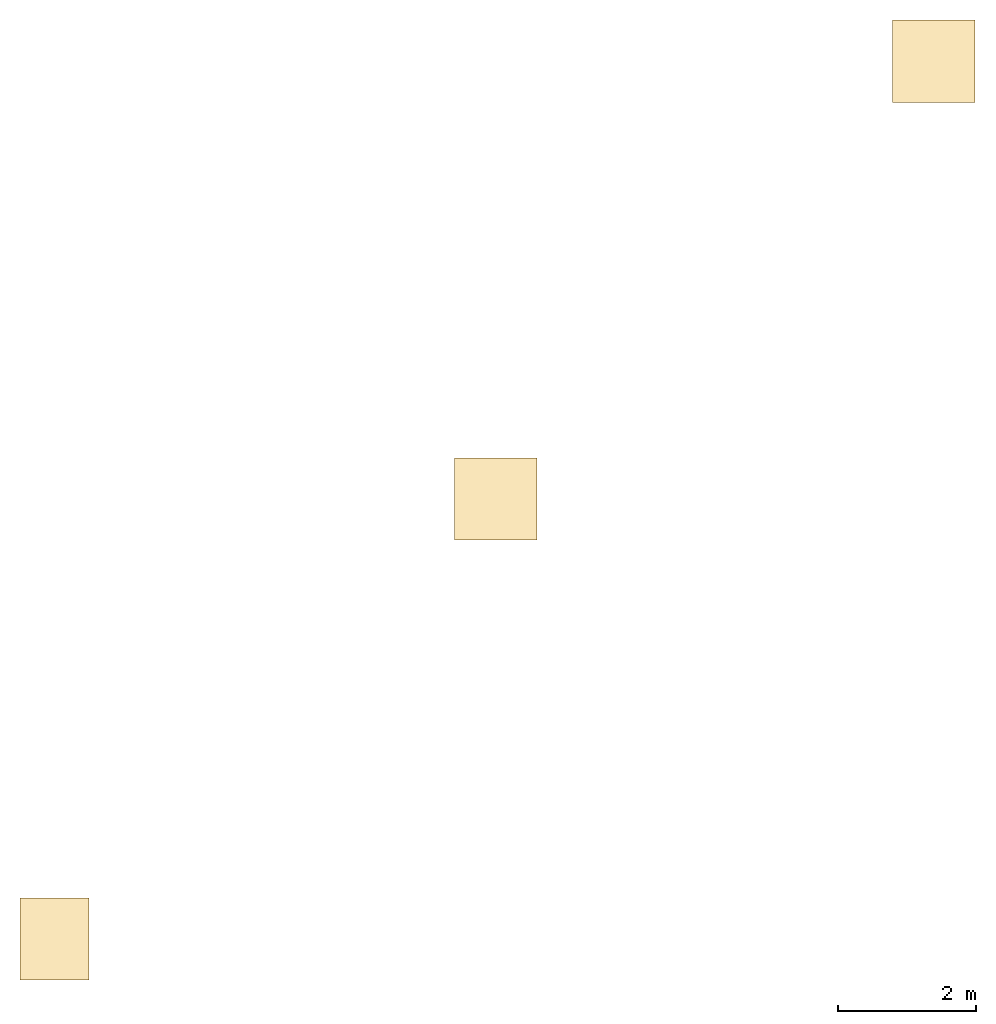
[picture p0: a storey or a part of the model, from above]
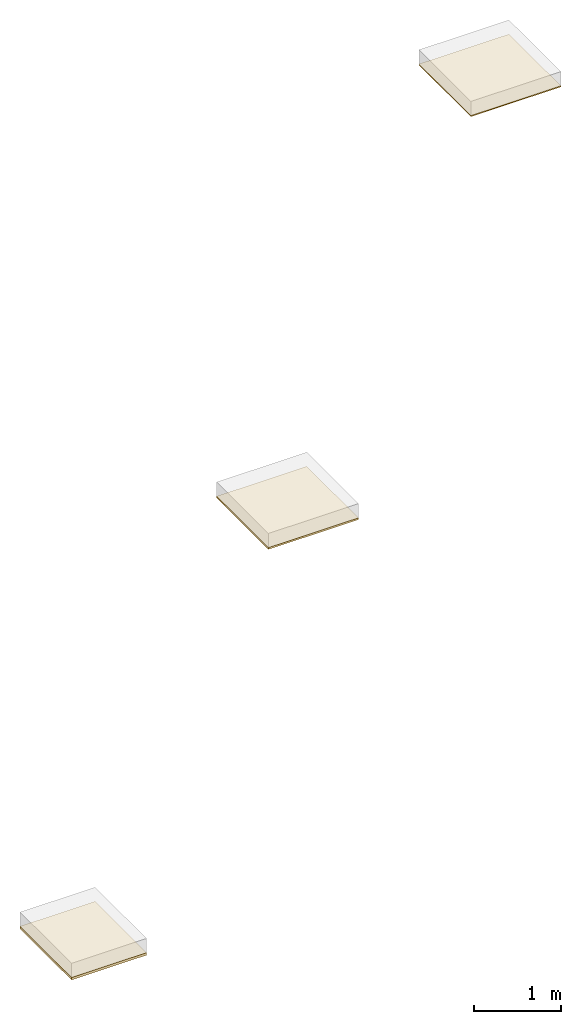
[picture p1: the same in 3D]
Properties of the parts of a building model (IFC2X3)

# File
Description: ViewDefinition [CoordinationView]
File name: 012345
Time: 2023-01-18T09:42:17
Written by: The EXPRESS Data Manager Version 5.02.0100.07 : 28 Aug 2013
Made in: 21.1.70.21 - Exporter 21.1.70.21 - Alternate UI 21.1.70.21
Comment: STEP Physical File produced by: The EXPRESS Data Manager Version 5.02.0100.07 : 28 Aug 2013 * Module: EDMstepFileFactory/EDMstandAlone * Creation date: Wed Jan 18 09:42:17 2023 * Host: BIM-LT03 * Database: C:\Users\DONNEE~1\AppData\Local\Temp\6dfd9f73-01cb-4fe2-bb7c-203e315a706e\6f2f6949-de90-4345-abf6-b3687df37d3c\ifc * Database version: 5507 * Database creation date: Wed Jan 18 09:42:17 2023 * Schema: IFC2X3 * Model: DataRepository.ifc * Model creation date: Wed Jan 18 09:42:17 2023 * Header model: DataRepository.ifc_HeaderModel * Header model creation date: Wed Jan 18 09:42:17 2023 * EDMuser: sdai-user * EDMgroup: sdai-group * License ID and type: 5605 : Permanent license. Expiry date: * EDMstepFileFactory options: 020000

# IfcProject, 012345
LongName: Cadix Project Naam; Phase: Cadix leeg V2.0

# IfcSite, Default
RefLatitude: 52, 3, 20, 225830; RefLongitude: 5, 6, 28, 692855; RefElevation: 0 mm
Pset_ProductRequirements - Category: Project Information

# IfcBuilding
Pset_BuildingCommon - NumberOfStoreys: 2
Pset_ProductRequirements - Category: Project Information

# IfcBuildingStorey: Level:niveau (2)
Pset_ProductRequirements - Category: Levels
Name | LongName = Pset_AirSideSystemInformation, Name = Pset_ProductRequirements, Name | Elevation (mm)
00 begane grond | 00 begane grond | -2.7707e-11
01 eerste verdieping | 01 eerste verdieping | 1200

# IfcCovering: Compound Ceiling:NLRS_45_CEI_Heraklith A2 afbouwpaneel 15x1200x600mm, Compound Ceiling:NLRS_45_CEI_Heraklith A2 afbouwpaneel 15x1200x600mm:888459
In: 01 eerste verdieping
Type - PredefinedType: CEILING
Type - Pset_CoveringCommon - Reference: Compound Ceiling:NLRS_45_CEI_Heraklith A2 afbouwpaneel 15x1200x600mm; TotalThickness: 15 mm
Type - Pset_ElementShading - Roughness: 304.8 mm
Type - Pset_ManufacturerTypeInformation - Manufacturer: Knauf Insulation B.V.
Type - Pset_ProductRequirements - Category: Ceilings
Type - Pset_QuantityTakeOff - Reference: Compound Ceiling:NLRS_45_CEI_Heraklith A2 afbouwpaneel 15x1200x600mm
Type - Ceiling Schedule LOD200 - Assembly Code: 45.0; Type Image: Raster image: Heraklith A2 Afbouwpaneel.jpg; Model: Heraklith® | A2 afbouwpaneel is een A2 houtwolcementpaneel; Manufacturer: Knauf Insulation B.V.; URL: www.heraklith.nl; Description: A2 afbouwpaneel - 15mm; phone: +31(0)162-421245; email: customerservice.nl@knaufinsulation.com; product URL: https://heraklith.nl/houtwol-producten/a2-afbouwpaneel; warmteweerstand: 0,15 (m2.K/W); NLRS_C_Code_Brandklasse: A2-s1,d0; brandweerstand: REI 60 mits verwerkt tegen massief beton conform classificatierapport nr 16210B / 16211B; geluidsabsorbtie: niet getest; DoP: W4302APCPR; NLRS_C_content_creator: Knauf Insulation; NLRS_C_content_versie: V1.0
Type - Pset_Ceiling Schedule LOD400 - gewicht KG/M2: 8.5; Assembly Code: 45.0; Type Image: Raster image: Heraklith A2 Afbouwpaneel.jpg; Model: Heraklith® | A2 afbouwpaneel is een A2 houtwolcementpaneel; Manufacturer: Knauf Insulation B.V.; URL: www.heraklith.nl; Description: A2 afbouwpaneel - 15mm; phone: +31(0)162-421245; email: customerservice.nl@knaufinsulation.com; product URL: https://heraklith.nl/houtwol-producten/a2-afbouwpaneel; warmteweerstand: 0,15 (m2.K/W); NLRS_C_Code_Brandklasse: A2-s1,d0; brandweerstand: REI 60 mits verwerkt tegen massief beton conform classificatierapport nr 16210B / 16211B; geluidsabsorbtie: niet getest; DoP: W4302APCPR; NLRS_C_content_creator: Knauf Insulation; NLRS_C_content_versie: V1.0; panelen per pallet: 70; pallet m2: 50.4 m2; vezelbreedte: standaard 2mm optie: 1mm; kleur: standaard natuurtint optie: Wit (RAL9003) / RAL; Druksterkte kPa: 200; Chloride gehalte: Cl3; Tolerantie: Dikte (T): (T1) +3/-2; Tolerantie: Lengte (L): (L2) +3/-5; Tolerantie: Breedte (W): (W1) +3/-3; Tolerantie: Haaksheid (S): (S2) ≤2; Tolerantie: Vlakheid (P): (P1) ≤6; Randafwerking: Isolatie: n.v.t.; Randafwerking: Houtwol: Facet: 5mm; CE-codering: WW-EN 13168-L2-W1-T1-S2-P2-CS(10/Y)200-Cl3
Classification: 45.0 (Uniformat); Material: Heraklith A2 afbouwpaneel - Houtwollaag - 1200x600mm 15 mm
Pset_CoveringCommon - Finish: Heraklith A2 afbouwpaneel - Houtwollaag - 1200x600mm;
Ceiling Schedule LOD200 - Type: Compound Ceiling: NLRS_45_CEI_Heraklith A2 afbouwpaneel 15x1200x600mm
Pset_Ceiling Schedule LOD400 - Type: Compound Ceiling: NLRS_45_CEI_Heraklith A2 afbouwpaneel 15x1200x600mm

# IfcCovering: Compound Ceiling:NLRS_45_CEI_Heraklith A2 afbouwpaneel 25x1200x600mm, Compound Ceiling:NLRS_45_CEI_Heraklith A2 afbouwpaneel 25x1200x600mm:912503
In: 01 eerste verdieping
Type - PredefinedType: CEILING
Type - Pset_CoveringCommon - Reference: Compound Ceiling:NLRS_45_CEI_Heraklith A2 afbouwpaneel 25x1200x600mm; TotalThickness: 25 mm
Type - Pset_ElementShading - Roughness: 304.8 mm
Type - Pset_ManufacturerTypeInformation - Manufacturer: Knauf Insulation B.V.
Type - Pset_ProductRequirements - Category: Ceilings
Type - Pset_QuantityTakeOff - Reference: Compound Ceiling:NLRS_45_CEI_Heraklith A2 afbouwpaneel 25x1200x600mm
Type - Ceiling Schedule LOD200 - Assembly Code: 45.0; Type Image: Raster image: Heraklith A2 Afbouwpaneel.jpg; Model: Heraklith® | A2 afbouwpaneel is een A2 houtwolcementpaneel; Manufacturer: Knauf Insulation B.V.; URL: www.heraklith.nl; Description: A2 afbouwpaneel - 25mm; phone: +31(0)162-421245; email: customerservice.nl@knaufinsulation.com; product URL: https://heraklith.nl/houtwol-producten/a2-afbouwpaneel; warmteweerstand: 0,25 (m2.K/W); NLRS_C_Code_Brandklasse: A2-s1,d0; brandweerstand: REI 60 mits verwerkt tegen massief beton conform classificatierapport nr 16210B / 16211B; geluidsabsorbtie: max. 0,90; DoP: W4302APCPR; NLRS_C_content_creator: Knauf Insulation; NLRS_C_content_versie: V1.0
Type - Pset_Ceiling Schedule LOD400 - Assembly Code: 45.0; Type Image: Raster image: Heraklith A2 Afbouwpaneel.jpg; Model: Heraklith® | A2 afbouwpaneel is een A2 houtwolcementpaneel; Manufacturer: Knauf Insulation B.V.; URL: www.heraklith.nl; Description: A2 afbouwpaneel - 25mm; phone: +31(0)162-421245; email: customerservice.nl@knaufinsulation.com; product URL: https://heraklith.nl/houtwol-producten/a2-afbouwpaneel; warmteweerstand: 0,25 (m2.K/W); NLRS_C_Code_Brandklasse: A2-s1,d0; brandweerstand: REI 60 mits verwerkt tegen massief beton conform classificatierapport nr 16210B / 16211B; geluidsabsorbtie: max. 0,90; DoP: W4302APCPR; NLRS_C_content_creator: Knauf Insulation; NLRS_C_content_versie: V1.0; gewicht KG/M2: 11.5; panelen per pallet: 40; pallet m2: 28.8 m2; vezelbreedte: standaard 2mm optie: 1mm; kleur: standaard natuurtint optie: Wit (RAL9003) / RAL; Druksterkte kPa: 200; Chloride gehalte: Cl3; Tolerantie: Dikte (T): (T1) +3/-2; Tolerantie: Lengte (L): (L2) +3/-5; Tolerantie: Breedte (W): (W1) +3/-3; Tolerantie: Haaksheid (S): (S2) ≤2; Tolerantie: Vlakheid (P): (P1) ≤6; Randafwerking: Isolatie: n.v.t.; Randafwerking: Houtwol: Facet: 5mm; CE-codering: WW-EN 13168-L2-W1-T1-S2-P2-CS(10/Y)200-Cl3
Classification: 45.0 (Uniformat); Material: Heraklith A2 afbouwpaneel - Houtwollaag - 1200x600mm 25 mm
Pset_CoveringCommon - Finish: Heraklith A2 afbouwpaneel - Houtwollaag - 1200x600mm;
Ceiling Schedule LOD200 - Type: Compound Ceiling: NLRS_45_CEI_Heraklith A2 afbouwpaneel 25x1200x600mm
Pset_Ceiling Schedule LOD400 - Type: Compound Ceiling: NLRS_45_CEI_Heraklith A2 afbouwpaneel 25x1200x600mm

# IfcCovering: Compound Ceiling:NLRS_45_CEI_Heraklith A2 afbouwpaneel 35x1000x600mm, Compound Ceiling:NLRS_45_CEI_Heraklith A2 afbouwpaneel 35x1000x600mm:914120
In: 01 eerste verdieping
Type - PredefinedType: CEILING
Type - Pset_CoveringCommon - Reference: Compound Ceiling:NLRS_45_CEI_Heraklith A2 afbouwpaneel 35x1000x600mm; TotalThickness: 35 mm
Type - Pset_ElementShading - Roughness: 304.8 mm
Type - Pset_ManufacturerTypeInformation - Manufacturer: Knauf Insulation B.V.
Type - Pset_ProductRequirements - Category: Ceilings
Type - Pset_QuantityTakeOff - Reference: Compound Ceiling:NLRS_45_CEI_Heraklith A2 afbouwpaneel 35x1000x600mm
Type - Ceiling Schedule LOD200 - Assembly Code: 45.0; Type Image: Raster image: Heraklith A2 Afbouwpaneel.jpg; Model: Heraklith® | A2 afbouwpaneel is een A2 houtwolcementpaneel; Manufacturer: Knauf Insulation B.V.; URL: www.heraklith.nl; Description: A2 afbouwpaneel - 35mm; phone: +31(0)162-421245; email: customerservice.nl@knaufinsulation.com; product URL: https://heraklith.nl/houtwol-producten/a2-afbouwpaneel; warmteweerstand: 0,40 (m2.K/W); NLRS_C_Code_Brandklasse: A2-s1,d0; brandweerstand: REI 60 mits verwerkt tegen massief beton conform classificatierapport nr 16210B / 16211B; geluidsabsorbtie: 0,40; DoP: W4302APCPR; NLRS_C_content_creator: Knauf Insulation; NLRS_C_content_versie: V1.0
Type - Pset_Ceiling Schedule LOD400 - Assembly Code: 45.0; Type Image: Raster image: Heraklith A2 Afbouwpaneel.jpg; Model: Heraklith® | A2 afbouwpaneel is een A2 houtwolcementpaneel; Manufacturer: Knauf Insulation B.V.; URL: www.heraklith.nl; Description: A2 afbouwpaneel - 35mm; phone: +31(0)162-421245; email: customerservice.nl@knaufinsulation.com; product URL: https://heraklith.nl/houtwol-producten/a2-afbouwpaneel; warmteweerstand: 0,40 (m2.K/W); NLRS_C_Code_Brandklasse: A2-s1,d0; brandweerstand: REI 60 mits verwerkt tegen massief beton conform classificatierapport nr 16210B / 16211B; geluidsabsorbtie: 0,40; DoP: W4302APCPR; NLRS_C_content_creator: Knauf Insulation; NLRS_C_content_versie: V1.0; gewicht KG/M2: 14.5; panelen per pallet: 30; pallet m2: 18 m2; vezelbreedte: standaard 2mm optie: 1mm; kleur: standaard natuurtint optie: Wit (RAL9003) / RAL; Druksterkte kPa: 150; Chloride gehalte: Cl3; Tolerantie: Dikte (T): (T1) +3/-2; Tolerantie: Lengte (L): (L2) +3/-5; Tolerantie: Breedte (W): (W1) +3/-3; Tolerantie: Haaksheid (S): (S2) ≤2; Tolerantie: Vlakheid (P): (P1) ≤6; Randafwerking: Isolatie: n.v.t.; Randafwerking: Houtwol: Facet: 5mm; CE-codering: WW-EN 13168-L2-W1-T1-S2-P2-CS(10/Y)200-Cl3
Classification: 45.0 (Uniformat); Material: Heraklith A2 afbouwpaneel - Houtwollaag - 1000x600mm 35 mm
Pset_CoveringCommon - Finish: Heraklith A2 afbouwpaneel - Houtwollaag - 1000x600mm;
Ceiling Schedule LOD200 - Type: Compound Ceiling: NLRS_45_CEI_Heraklith A2 afbouwpaneel 35x1000x600mm
Pset_Ceiling Schedule LOD400 - Type: Compound Ceiling: NLRS_45_CEI_Heraklith A2 afbouwpaneel 35x1000x600mm

# IfcSlab: Floor:Generic 200mm (6)
Type - PredefinedType: FLOOR; Material: Concrete, Precast Panels 200 mm
Type - Pset_ElementShading - Roughness: 914.4 mm
Type - Pset_ProductRequirements - Category: Floors
Type - Pset_QuantityTakeOff - Reference: Floor:Generic 200mm
Type - Pset_ReinforcementBarPitchOfSlab - Reference: Floor:Generic 200mm
Type - Pset_SlabCommon - IsExternal: no; Reference: Floor:Generic 200mm; ThermalTransmittance: 5.23 kg/K/s3
Pset_QuantityTakeOff - sets with these values: 2
Pset_SlabCommon - LoadBearing: no; PitchAngle: 0 deg
Name (Floor:Generic 200mm:...) | In
915309 | 00 begane grond
915454 | 00 begane grond
915523 | 00 begane grond
916757 | 01 eerste verdieping
916812 | 01 eerste verdieping
916986 | 01 eerste verdieping

# IfcSlab: Floor:NLRS_23_FL_Heraklith A2 afbouwpaneel 15x1200x600mm, Floor:NLRS_23_FL_Heraklith A2 afbouwpaneel 15x1200x600mm:889765
In: 00 begane grond
Type - PredefinedType: FLOOR; Material: Heraklith A2 afbouwpaneel - Houtwollaag - 1200x600mm 15 mm
Type - Pset_ElementShading - Roughness: 304.8 mm
Type - Pset_ManufacturerTypeInformation - Manufacturer: Knauf Insulation B.V.
Type - Pset_ProductRequirements - Category: Floors
Type - Pset_QuantityTakeOff - Reference: Floor:NLRS_23_FL_Heraklith A2 afbouwpaneel 15x1200x600mm
Type - Pset_ReinforcementBarPitchOfSlab - Description: A2 afbouwpaneel - 15mm; Reference: Floor:NLRS_23_FL_Heraklith A2 afbouwpaneel 15x1200x600mm
Type - Pset_SlabCommon - IsExternal: no; Reference: Floor:NLRS_23_FL_Heraklith A2 afbouwpaneel 15x1200x600mm; ThermalTransmittance: 56.6667 kg/K/s3
Type - Floor Schedule LOD200 - Assembly Code: 23.0; Type Image: Raster image: Heraklith A2 Afbouwpaneel.jpg; Model: Heraklith® | A2 afbouwpaneel is een A2 houtwolcementpaneel; Manufacturer: Knauf Insulation B.V.; URL: www.heraklith.nl; Description: A2 afbouwpaneel - 15mm; phone: +31(0)162-421245; email: customerservice.nl@knaufinsulation.com; product URL: https://heraklith.nl/houtwol-producten/a2-afbouwpaneel; warmteweerstand: 0,15 (m2.K/W); NLRS_C_Code_Brandklasse: A2-s1,d0; brandweerstand: REI 60 mits verwerkt tegen massief beton conform classificatierapport nr 16210B / 16211B; geluidsabsorbtie: niet getest; DoP: W4302APCPR; NLRS_C_content_creator: Knauf Insulation; NLRS_C_content_versie: V1.0
Type - Pset_Floor Schedule LOD400 - gewicht KG/M2: 8.5; Assembly Code: 23.0; Type Image: Raster image: Heraklith A2 Afbouwpaneel.jpg; Model: Heraklith® | A2 afbouwpaneel is een A2 houtwolcementpaneel; Manufacturer: Knauf Insulation B.V.; URL: www.heraklith.nl; Description: A2 afbouwpaneel - 15mm; phone: +31(0)162-421245; email: customerservice.nl@knaufinsulation.com; product URL: https://heraklith.nl/houtwol-producten/a2-afbouwpaneel; warmteweerstand: 0,15 (m2.K/W); NLRS_C_Code_Brandklasse: A2-s1,d0; brandweerstand: REI 60 mits verwerkt tegen massief beton conform classificatierapport nr 16210B / 16211B; geluidsabsorbtie: niet getest; DoP: W4302APCPR; NLRS_C_content_creator: Knauf Insulation; NLRS_C_content_versie: V1.0; panelen per pallet: 70; pallet m2: 50.4 m2; vezelbreedte: standaard 2mm optie: 1mm; kleur: standaard natuurtint optie: Wit (RAL9003) / RAL; Druksterkte kPa: 200; Chloride gehalte: Cl3; Tolerantie: Dikte (T): (T1) +3/-2; Tolerantie: Lengte (L): (L2) +3/-5; Tolerantie: Breedte (W): (W1) +3/-3; Tolerantie: Haaksheid (S): (S2) ≤2; Tolerantie: Vlakheid (P): (P1) ≤6; Randafwerking: Isolatie: n.v.t.; Randafwerking: Houtwol: Facet: 5mm; CE-codering: WW-EN 13168-L2-W1-T1-S2-P2-CS(10/Y)200-Cl3
Classification: 23.0 (Uniformat)
Pset_SlabCommon - LoadBearing: no; IsExternal: yes; PitchAngle: 0 deg
Floor Schedule LOD200 - Type: Floor: NLRS_23_FL_Heraklith A2 afbouwpaneel 15x1200x600mm
Pset_Floor Schedule LOD400 - Type: Floor: NLRS_23_FL_Heraklith A2 afbouwpaneel 15x1200x600mm

# IfcSlab: Floor:NLRS_23_FL_Heraklith A2 afbouwpaneel 25x1200x600mm, Floor:NLRS_23_FL_Heraklith A2 afbouwpaneel 25x1200x600mm:912512
In: 00 begane grond
Type - PredefinedType: FLOOR; Material: Heraklith A2 afbouwpaneel - Houtwollaag - 1200x600mm 25 mm
Type - Pset_ElementShading - Roughness: 304.8 mm
Type - Pset_ManufacturerTypeInformation - Manufacturer: Knauf Insulation B.V.
Type - Pset_ProductRequirements - Category: Floors
Type - Pset_QuantityTakeOff - Reference: Floor:NLRS_23_FL_Heraklith A2 afbouwpaneel 25x1200x600mm
Type - Pset_ReinforcementBarPitchOfSlab - Description: A2 afbouwpaneel - 25mm; Reference: Floor:NLRS_23_FL_Heraklith A2 afbouwpaneel 25x1200x600mm
Type - Pset_SlabCommon - IsExternal: no; Reference: Floor:NLRS_23_FL_Heraklith A2 afbouwpaneel 25x1200x600mm; ThermalTransmittance: 34 kg/K/s3
Type - Floor Schedule LOD200 - Assembly Code: 23.0; Type Image: Raster image: Heraklith A2 Afbouwpaneel.jpg; Model: Heraklith® | A2 afbouwpaneel is een A2 houtwolcementpaneel; Manufacturer: Knauf Insulation B.V.; URL: www.heraklith.nl; Description: A2 afbouwpaneel - 25mm; phone: +31(0)162-421245; email: customerservice.nl@knaufinsulation.com; product URL: https://heraklith.nl/houtwol-producten/a2-afbouwpaneel; warmteweerstand: 0,25 (m2.K/W); NLRS_C_Code_Brandklasse: A2-s1,d0; brandweerstand: REI 60 mits verwerkt tegen massief beton conform classificatierapport nr 16210B / 16211B; geluidsabsorbtie: max. 0,90; DoP: W4302APCPR; NLRS_C_content_creator: Knauf Insulation; NLRS_C_content_versie: V1.0
Type - Pset_Floor Schedule LOD400 - Assembly Code: 23.0; Type Image: Raster image: Heraklith A2 Afbouwpaneel.jpg; Model: Heraklith® | A2 afbouwpaneel is een A2 houtwolcementpaneel; Manufacturer: Knauf Insulation B.V.; URL: www.heraklith.nl; Description: A2 afbouwpaneel - 25mm; phone: +31(0)162-421245; email: customerservice.nl@knaufinsulation.com; product URL: https://heraklith.nl/houtwol-producten/a2-afbouwpaneel; warmteweerstand: 0,25 (m2.K/W); NLRS_C_Code_Brandklasse: A2-s1,d0; brandweerstand: REI 60 mits verwerkt tegen massief beton conform classificatierapport nr 16210B / 16211B; geluidsabsorbtie: max. 0,90; DoP: W4302APCPR; NLRS_C_content_creator: Knauf Insulation; NLRS_C_content_versie: V1.0; gewicht KG/M2: 11.5; panelen per pallet: 40; pallet m2: 28.8 m2; vezelbreedte: standaard 2mm optie: 1mm; kleur: standaard natuurtint optie: Wit (RAL9003) / RAL; Druksterkte kPa: 200; Chloride gehalte: Cl3; Tolerantie: Dikte (T): (T1) +3/-2; Tolerantie: Lengte (L): (L2) +3/-5; Tolerantie: Breedte (W): (W1) +3/-3; Tolerantie: Haaksheid (S): (S2) ≤2; Tolerantie: Vlakheid (P): (P1) ≤6; Randafwerking: Isolatie: n.v.t.; Randafwerking: Houtwol: Facet: 5mm; CE-codering: WW-EN 13168-L2-W1-T1-S2-P2-CS(10/Y)200-Cl3
Classification: 23.0 (Uniformat)
Pset_SlabCommon - LoadBearing: no; IsExternal: yes; PitchAngle: 0 deg
Floor Schedule LOD200 - Type: Floor: NLRS_23_FL_Heraklith A2 afbouwpaneel 25x1200x600mm
Pset_Floor Schedule LOD400 - Type: Floor: NLRS_23_FL_Heraklith A2 afbouwpaneel 25x1200x600mm

# IfcSlab: Floor:NLRS_23_FL_Heraklith A2 afbouwpaneel 35x1000x600mm, Floor:NLRS_23_FL_Heraklith A2 afbouwpaneel 35x1000x600mm:914109
In: 00 begane grond
Type - PredefinedType: FLOOR; Material: Heraklith A2 afbouwpaneel - Houtwollaag - 1000x600mm 35 mm
Type - Pset_ElementShading - Roughness: 304.8 mm
Type - Pset_ManufacturerTypeInformation - Manufacturer: Knauf Insulation B.V.
Type - Pset_ProductRequirements - Category: Floors
Type - Pset_QuantityTakeOff - Reference: Floor:NLRS_23_FL_Heraklith A2 afbouwpaneel 35x1000x600mm
Type - Pset_ReinforcementBarPitchOfSlab - Description: A2 afbouwpaneel - 35mm; Reference: Floor:NLRS_23_FL_Heraklith A2 afbouwpaneel 35x1000x600mm
Type - Pset_SlabCommon - IsExternal: no; Reference: Floor:NLRS_23_FL_Heraklith A2 afbouwpaneel 35x1000x600mm; ThermalTransmittance: 24.2857 kg/K/s3
Type - Floor Schedule LOD200 - Assembly Code: 23.0; Type Image: Raster image: Heraklith A2 Afbouwpaneel.jpg; Model: Heraklith® | A2 afbouwpaneel is een A2 houtwolcementpaneel; Manufacturer: Knauf Insulation B.V.; URL: www.heraklith.nl; Description: A2 afbouwpaneel - 35mm; phone: +31(0)162-421245; email: customerservice.nl@knaufinsulation.com; product URL: https://heraklith.nl/houtwol-producten/a2-afbouwpaneel; warmteweerstand: 0,40 (m2.K/W); NLRS_C_Code_Brandklasse: A2-s1,d0; brandweerstand: REI 60 mits verwerkt tegen massief beton conform classificatierapport nr 16210B / 16211B; geluidsabsorbtie: 0,40; DoP: W4302APCPR; NLRS_C_content_creator: Knauf Insulation; NLRS_C_content_versie: V1.0
Type - Pset_Floor Schedule LOD400 - Assembly Code: 23.0; Type Image: Raster image: Heraklith A2 Afbouwpaneel.jpg; Model: Heraklith® | A2 afbouwpaneel is een A2 houtwolcementpaneel; Manufacturer: Knauf Insulation B.V.; URL: www.heraklith.nl; Description: A2 afbouwpaneel - 35mm; phone: +31(0)162-421245; email: customerservice.nl@knaufinsulation.com; product URL: https://heraklith.nl/houtwol-producten/a2-afbouwpaneel; warmteweerstand: 0,40 (m2.K/W); NLRS_C_Code_Brandklasse: A2-s1,d0; brandweerstand: REI 60 mits verwerkt tegen massief beton conform classificatierapport nr 16210B / 16211B; geluidsabsorbtie: 0,40; DoP: W4302APCPR; NLRS_C_content_creator: Knauf Insulation; NLRS_C_content_versie: V1.0; gewicht KG/M2: 14.5; panelen per pallet: 30; pallet m2: 18 m2; vezelbreedte: standaard 2mm optie: 1mm; kleur: standaard natuurtint optie: Wit (RAL9003) / RAL; Druksterkte kPa: 150; Chloride gehalte: Cl3; Tolerantie: Dikte (T): (T1) +3/-2; Tolerantie: Lengte (L): (L2) +3/-5; Tolerantie: Breedte (W): (W1) +3/-3; Tolerantie: Haaksheid (S): (S2) ≤2; Tolerantie: Vlakheid (P): (P1) ≤6; Randafwerking: Isolatie: n.v.t.; Randafwerking: Houtwol: Facet: 5mm; CE-codering: WW-EN 13168-L2-W1-T1-S2-P2-CS(10/Y)200-Cl3
Classification: 23.0 (Uniformat)
Pset_SlabCommon - LoadBearing: no; IsExternal: yes; PitchAngle: 0 deg
Floor Schedule LOD200 - Type: Floor: NLRS_23_FL_Heraklith A2 afbouwpaneel 35x1000x600mm
Pset_Floor Schedule LOD400 - Type: Floor: NLRS_23_FL_Heraklith A2 afbouwpaneel 35x1000x600mm

# IfcWallStandardCase: Basic Wall:Generic_100mm (6)
In: 00 begane grond
Type - PredefinedType: STANDARD; Material: Concrete, Precast Panels 100 mm
Type - Pset_ElementShading - Roughness: 914.4 mm
Type - Pset_ProductRequirements - Category: Walls
Type - Pset_QuantityTakeOff - Reference: Basic Wall:Generic_100mm
Type - Pset_ReinforcementBarPitchOfWall - Reference: Basic Wall:Generic_100mm
Type - Pset_WallCommon - IsExternal: no; Reference: Basic Wall:Generic_100mm; ThermalTransmittance: 10.46 kg/K/s3
Pset_QuantityTakeOff - sets with these values: 2
Pset_WallCommon - ExtendToStructure: no; LoadBearing: no; IsExternal: yes
Name (Basic Wall:Generic_100mm:...)
915746
915832
916208
916288
916512
916584

# IfcWallStandardCase: Basic Wall:NLRS_41_WA_Heraklith A2 afbouwpaneel 15x1200x600mm, Basic Wall:NLRS_41_WA_Heraklith A2 afbouwpaneel 15x1200x600mm:888766
In: 00 begane grond
Type - PredefinedType: STANDARD; Material: Heraklith A2 afbouwpaneel - Houtwollaag - 1200x600mm 15 mm
Type - Pset_ElementShading - Roughness: 304.8 mm
Type - Pset_ManufacturerTypeInformation - Manufacturer: Knauf Insulation B.V.
Type - Pset_ProductRequirements - Category: Walls
Type - Pset_QuantityTakeOff - Reference: Basic Wall:NLRS_41_WA_Heraklith A2 afbouwpaneel 15x1200x600mm
Type - Pset_ReinforcementBarPitchOfWall - Description: A2 afbouwpaneel - 15mm; Reference: Basic Wall:NLRS_41_WA_Heraklith A2 afbouwpaneel 15x1200x600mm
Type - Pset_WallCommon - Reference: Basic Wall:NLRS_41_WA_Heraklith A2 afbouwpaneel 15x1200x600mm; ThermalTransmittance: 56.6667 kg/K/s3; IsExternal: no
Type - Wall Schedule LOD200 - Assembly Code: 41.10; Type Image: Raster image: Heraklith A2 Afbouwpaneel.jpg; Model: Heraklith® | A2 afbouwpaneel is een A2 houtwolcementpaneel; Manufacturer: Knauf Insulation B.V.; URL: www.heraklith.nl; Description: A2 afbouwpaneel - 15mm; phone: +31(0)162-421245; email: customerservice.nl@knaufinsulation.com; product URL: https://heraklith.nl/houtwol-producten/a2-afbouwpaneel; warmteweerstand: 0,15 (m2.K/W); NLRS_C_Code_Brandklasse: A2-s1,d0; brandweerstand: REI 60 mits verwerkt tegen massief beton conform classificatierapport nr 16210B / 16211B; geluidsabsorbtie: niet getest; DoP: W4302APCPR; NLRS_C_content_creator: Knauf Insulation; NLRS_C_content_versie: V1.0
Type - Pset_Wall Schedule LOD400 - gewicht KG/M2: 8.5; Assembly Code: 41.10; Type Image: Raster image: Heraklith A2 Afbouwpaneel.jpg; Model: Heraklith® | A2 afbouwpaneel is een A2 houtwolcementpaneel; Manufacturer: Knauf Insulation B.V.; URL: www.heraklith.nl; Description: A2 afbouwpaneel - 15mm; phone: +31(0)162-421245; email: customerservice.nl@knaufinsulation.com; product URL: https://heraklith.nl/houtwol-producten/a2-afbouwpaneel; warmteweerstand: 0,15 (m2.K/W); NLRS_C_Code_Brandklasse: A2-s1,d0; brandweerstand: REI 60 mits verwerkt tegen massief beton conform classificatierapport nr 16210B / 16211B; geluidsabsorbtie: niet getest; DoP: W4302APCPR; NLRS_C_content_creator: Knauf Insulation; NLRS_C_content_versie: V1.0; panelen per pallet: 70; pallet m2: 50.4 m2; vezelbreedte: standaard 2mm optie: 1mm; kleur: standaard natuurtint optie: Wit (RAL9003) / RAL; Druksterkte kPa: 200; Chloride gehalte: Cl3; Tolerantie: Dikte (T): (T1) +3/-2; Tolerantie: Lengte (L): (L2) +3/-5; Tolerantie: Breedte (W): (W1) +3/-3; Tolerantie: Haaksheid (S): (S2) ≤2; Tolerantie: Vlakheid (P): (P1) ≤6; Randafwerking: Isolatie: n.v.t.; Randafwerking: Houtwol: Facet: 5mm; CE-codering: WW-EN 13168-L2-W1-T1-S2-P2-CS(10/Y)200-Cl3
Classification: 41.10 (Uniformat)
Pset_WallCommon - ExtendToStructure: no; LoadBearing: no
Wall Schedule LOD200 - Type: Basic Wall: NLRS_41_WA_Heraklith A2 afbouwpaneel 15x1200x600mm
Pset_Wall Schedule LOD400 - Type: Basic Wall: NLRS_41_WA_Heraklith A2 afbouwpaneel 15x1200x600mm

# IfcWallStandardCase: Basic Wall:NLRS_41_WA_Heraklith A2 afbouwpaneel 25x1200x600mm, Basic Wall:NLRS_41_WA_Heraklith A2 afbouwpaneel 25x1200x600mm:912508
In: 00 begane grond
Type - PredefinedType: STANDARD; Material: Heraklith A2 afbouwpaneel - Houtwollaag - 1200x600mm 25 mm
Type - Pset_ElementShading - Roughness: 304.8 mm
Type - Pset_ManufacturerTypeInformation - Manufacturer: Knauf Insulation B.V.
Type - Pset_ProductRequirements - Category: Walls
Type - Pset_QuantityTakeOff - Reference: Basic Wall:NLRS_41_WA_Heraklith A2 afbouwpaneel 25x1200x600mm
Type - Pset_ReinforcementBarPitchOfWall - Description: A2 afbouwpaneel - 25mm; Reference: Basic Wall:NLRS_41_WA_Heraklith A2 afbouwpaneel 25x1200x600mm
Type - Pset_WallCommon - IsExternal: no; Reference: Basic Wall:NLRS_41_WA_Heraklith A2 afbouwpaneel 25x1200x600mm; ThermalTransmittance: 34 kg/K/s3
Type - Wall Schedule LOD200 - Assembly Code: 41.10; Type Image: Raster image: Heraklith A2 Afbouwpaneel.jpg; Model: Heraklith® | A2 afbouwpaneel is een A2 houtwolcementpaneel; Manufacturer: Knauf Insulation B.V.; URL: www.heraklith.nl; Description: A2 afbouwpaneel - 25mm; phone: +31(0)162-421245; email: customerservice.nl@knaufinsulation.com; product URL: https://heraklith.nl/houtwol-producten/a2-afbouwpaneel; warmteweerstand: 0,25 (m2.K/W) v; NLRS_C_Code_Brandklasse: A2-s1,d0; brandweerstand: REI 60 mits verwerkt tegen massief beton conform classificatierapport nr 16210B / 16211B; geluidsabsorbtie: max. 0,90; DoP: W4302APCPR; NLRS_C_content_creator: Knauf Insulation; NLRS_C_content_versie: V1.0
Type - Pset_Wall Schedule LOD400 - Assembly Code: 41.10; Type Image: Raster image: Heraklith A2 Afbouwpaneel.jpg; Model: Heraklith® | A2 afbouwpaneel is een A2 houtwolcementpaneel; Manufacturer: Knauf Insulation B.V.; URL: www.heraklith.nl; Description: A2 afbouwpaneel - 25mm; phone: +31(0)162-421245; email: customerservice.nl@knaufinsulation.com; product URL: https://heraklith.nl/houtwol-producten/a2-afbouwpaneel; warmteweerstand: 0,25 (m2.K/W) v; NLRS_C_Code_Brandklasse: A2-s1,d0; brandweerstand: REI 60 mits verwerkt tegen massief beton conform classificatierapport nr 16210B / 16211B; geluidsabsorbtie: max. 0,90; DoP: W4302APCPR; NLRS_C_content_creator: Knauf Insulation; NLRS_C_content_versie: V1.0; gewicht KG/M2: 11.5; panelen per pallet: 40; pallet m2: 28.8 m2; vezelbreedte: standaard 2mm optie: 1mm; kleur: standaard natuurtint optie: Wit (RAL9003) / RAL; Druksterkte kPa: 200; Chloride gehalte: Cl3; Tolerantie: Dikte (T): (T1) +3/-2; Tolerantie: Lengte (L): (L2) +3/-5; Tolerantie: Breedte (W): (W1) +3/-3; Tolerantie: Haaksheid (S): (S2) ≤2; Tolerantie: Vlakheid (P): (P1) ≤6; Randafwerking: Isolatie: n.v.t.; Randafwerking: Houtwol: Facet: 5mm; CE-codering: WW-EN 13168-L2-W1-T1-S2-P2-CS(10/Y)200-Cl3
Classification: 41.10 (Uniformat)
Pset_WallCommon - ExtendToStructure: no; LoadBearing: no; IsExternal: yes
Wall Schedule LOD200 - Type: Basic Wall: NLRS_41_WA_Heraklith A2 afbouwpaneel 25x1200x600mm
Pset_Wall Schedule LOD400 - Type: Basic Wall: NLRS_41_WA_Heraklith A2 afbouwpaneel 25x1200x600mm

# IfcWallStandardCase: Basic Wall:NLRS_41_WA_Heraklith A2 afbouwpaneel 35x1000x600mm, Basic Wall:NLRS_41_WA_Heraklith A2 afbouwpaneel 35x1000x600mm:914281
In: 00 begane grond
Type - PredefinedType: STANDARD; Material: Heraklith A2 afbouwpaneel - Houtwollaag - 1000x600mm 35 mm
Type - Pset_ElementShading - Roughness: 304.8 mm
Type - Pset_ManufacturerTypeInformation - Manufacturer: Knauf Insulation B.V.
Type - Pset_ProductRequirements - Category: Walls
Type - Pset_QuantityTakeOff - Reference: Basic Wall:NLRS_41_WA_Heraklith A2 afbouwpaneel 35x1000x600mm
Type - Pset_ReinforcementBarPitchOfWall - Description: A2 afbouwpaneel - 35mm; Reference: Basic Wall:NLRS_41_WA_Heraklith A2 afbouwpaneel 35x1000x600mm
Type - Pset_WallCommon - IsExternal: no; Reference: Basic Wall:NLRS_41_WA_Heraklith A2 afbouwpaneel 35x1000x600mm; ThermalTransmittance: 24.2857 kg/K/s3
Type - Wall Schedule LOD200 - Assembly Code: 41.10; Type Image: Raster image: Heraklith A2 Afbouwpaneel.jpg; Model: Heraklith® | A2 afbouwpaneel is een A2 houtwolcementpaneel; Manufacturer: Knauf Insulation B.V.; URL: www.heraklith.nl; Description: A2 afbouwpaneel - 35mm; phone: +31(0)162-421245; email: customerservice.nl@knaufinsulation.com; product URL: https://heraklith.nl/houtwol-producten/a2-afbouwpaneel; warmteweerstand: 0,40 (m2.K/W); NLRS_C_Code_Brandklasse: A2-s1,d0; brandweerstand: REI 60 mits verwerkt tegen massief beton conform classificatierapport nr 16210B / 16211B; geluidsabsorbtie: 0,40; DoP: W4302APCPR; NLRS_C_content_creator: Knauf Insulation; NLRS_C_content_versie: V1.0
Type - Pset_Wall Schedule LOD400 - Assembly Code: 41.10; Type Image: Raster image: Heraklith A2 Afbouwpaneel.jpg; Model: Heraklith® | A2 afbouwpaneel is een A2 houtwolcementpaneel; Manufacturer: Knauf Insulation B.V.; URL: www.heraklith.nl; Description: A2 afbouwpaneel - 35mm; phone: +31(0)162-421245; email: customerservice.nl@knaufinsulation.com; product URL: https://heraklith.nl/houtwol-producten/a2-afbouwpaneel; warmteweerstand: 0,40 (m2.K/W); NLRS_C_Code_Brandklasse: A2-s1,d0; brandweerstand: REI 60 mits verwerkt tegen massief beton conform classificatierapport nr 16210B / 16211B; geluidsabsorbtie: 0,40; DoP: W4302APCPR; NLRS_C_content_creator: Knauf Insulation; NLRS_C_content_versie: V1.0; gewicht KG/M2: 14.5; panelen per pallet: 30; pallet m2: 18 m2; vezelbreedte: standaard 2mm optie: 1mm; kleur: standaard natuurtint optie: Wit (RAL9003) / RAL; Druksterkte kPa: 150; Chloride gehalte: Cl3; Tolerantie: Dikte (T): (T1) +3/-2; Tolerantie: Lengte (L): (L2) +3/-5; Tolerantie: Breedte (W): (W1) +3/-3; Tolerantie: Haaksheid (S): (S2) ≤2; Tolerantie: Vlakheid (P): (P1) ≤6; Randafwerking: Isolatie: n.v.t.; Randafwerking: Houtwol: Facet: 5mm; CE-codering: WW-EN 13168-L2-W1-T1-S2-P2-CS(10/Y)200-Cl3
Classification: 41.10 (Uniformat)
Pset_WallCommon - ExtendToStructure: no; LoadBearing: no; IsExternal: yes
Wall Schedule LOD200 - Type: Basic Wall: NLRS_41_WA_Heraklith A2 afbouwpaneel 35x1000x600mm
Pset_Wall Schedule LOD400 - Type: Basic Wall: NLRS_41_WA_Heraklith A2 afbouwpaneel 35x1000x600mm

# IfcWallStandardCase: Basic Wall:NLRS_42_WA_Heraklith A2 afbouwpaneel 15x1200x600mm, Basic Wall:NLRS_42_WA_Heraklith A2 afbouwpaneel 15x1200x600mm:890945
In: 00 begane grond
Type - PredefinedType: STANDARD; Material: Heraklith A2 afbouwpaneel - Houtwollaag - 1200x600mm 15 mm
Type - Pset_ElementShading - Roughness: 304.8 mm
Type - Pset_ManufacturerTypeInformation - Manufacturer: Knauf Insulation B.V.
Type - Pset_ProductRequirements - Category: Walls
Type - Pset_QuantityTakeOff - Reference: Basic Wall:NLRS_42_WA_Heraklith A2 afbouwpaneel 15x1200x600mm
Type - Pset_ReinforcementBarPitchOfWall - Description: A2 afbouwpaneel - 15mm; Reference: Basic Wall:NLRS_42_WA_Heraklith A2 afbouwpaneel 15x1200x600mm
Type - Pset_WallCommon - IsExternal: no; Reference: Basic Wall:NLRS_42_WA_Heraklith A2 afbouwpaneel 15x1200x600mm; ThermalTransmittance: 56.6667 kg/K/s3
Type - Wall Schedule LOD200 - Assembly Code: 42.10; Type Image: Raster image: Heraklith A2 Afbouwpaneel.jpg; Model: Heraklith® | A2 afbouwpaneel is een A2 houtwolcementpaneel; Manufacturer: Knauf Insulation B.V.; URL: www.heraklith.nl; Description: A2 afbouwpaneel - 15mm; phone: +31(0)162-421245; email: customerservice.nl@knaufinsulation.com; product URL: https://heraklith.nl/houtwol-producten/a2-afbouwpaneel; warmteweerstand: 0,15 (m2.K/W); NLRS_C_Code_Brandklasse: A2-s1,d0; brandweerstand: REI 60 mits verwerkt tegen massief beton conform classificatierapport nr 16210B / 16211B; geluidsabsorbtie: niet getest; DoP: W4302APCPR; NLRS_C_content_creator: Knauf Insulation; NLRS_C_content_versie: V1.0
Type - Pset_Wall Schedule LOD400 - gewicht KG/M2: 8.5; Assembly Code: 42.10; Type Image: Raster image: Heraklith A2 Afbouwpaneel.jpg; Model: Heraklith® | A2 afbouwpaneel is een A2 houtwolcementpaneel; Manufacturer: Knauf Insulation B.V.; URL: www.heraklith.nl; Description: A2 afbouwpaneel - 15mm; phone: +31(0)162-421245; email: customerservice.nl@knaufinsulation.com; product URL: https://heraklith.nl/houtwol-producten/a2-afbouwpaneel; warmteweerstand: 0,15 (m2.K/W); NLRS_C_Code_Brandklasse: A2-s1,d0; brandweerstand: REI 60 mits verwerkt tegen massief beton conform classificatierapport nr 16210B / 16211B; geluidsabsorbtie: niet getest; DoP: W4302APCPR; NLRS_C_content_creator: Knauf Insulation; NLRS_C_content_versie: V1.0; panelen per pallet: 70; pallet m2: 50.4 m2; vezelbreedte: standaard 2mm optie: 1mm; kleur: standaard natuurtint optie: Wit (RAL9003) / RAL; Druksterkte kPa: 200; Chloride gehalte: Cl3; Tolerantie: Dikte (T): (T1) +3/-2; Tolerantie: Lengte (L): (L2) +3/-5; Tolerantie: Breedte (W): (W1) +3/-3; Tolerantie: Haaksheid (S): (S2) ≤2; Tolerantie: Vlakheid (P): (P1) ≤6; Randafwerking: Isolatie: n.v.t.; Randafwerking: Houtwol: Facet: 5mm; CE-codering: WW-EN 13168-L2-W1-T1-S2-P2-CS(10/Y)200-Cl3
Classification: 42.10 (Uniformat)
Pset_WallCommon - ExtendToStructure: no; LoadBearing: no
Wall Schedule LOD200 - Type: Basic Wall: NLRS_42_WA_Heraklith A2 afbouwpaneel 15x1200x600mm
Pset_Wall Schedule LOD400 - Type: Basic Wall: NLRS_42_WA_Heraklith A2 afbouwpaneel 15x1200x600mm

# IfcWallStandardCase: Basic Wall:NLRS_42_WA_Heraklith A2 afbouwpaneel 25x1200x600mm, Basic Wall:NLRS_42_WA_Heraklith A2 afbouwpaneel 25x1200x600mm:912518
In: 00 begane grond
Type - PredefinedType: STANDARD; Material: Heraklith A2 afbouwpaneel - Houtwollaag - 1200x600mm 25 mm
Type - Pset_ElementShading - Roughness: 304.8 mm
Type - Pset_ManufacturerTypeInformation - Manufacturer: Knauf Insulation B.V.
Type - Pset_ProductRequirements - Category: Walls
Type - Pset_QuantityTakeOff - Reference: Basic Wall:NLRS_42_WA_Heraklith A2 afbouwpaneel 25x1200x600mm
Type - Pset_ReinforcementBarPitchOfWall - Description: A2 afbouwpaneel - 25mm; Reference: Basic Wall:NLRS_42_WA_Heraklith A2 afbouwpaneel 25x1200x600mm
Type - Pset_WallCommon - IsExternal: no; Reference: Basic Wall:NLRS_42_WA_Heraklith A2 afbouwpaneel 25x1200x600mm; ThermalTransmittance: 34 kg/K/s3
Type - Wall Schedule LOD200 - Assembly Code: 42.10; Type Image: Raster image: Heraklith A2 Afbouwpaneel.jpg; Model: Heraklith® | A2 afbouwpaneel is een A2 houtwolcementpaneel; Manufacturer: Knauf Insulation B.V.; URL: www.heraklith.nl; Description: A2 afbouwpaneel - 25mm; phone: +31(0)162-421245; email: customerservice.nl@knaufinsulation.com; product URL: https://heraklith.nl/houtwol-producten/a2-afbouwpaneel; warmteweerstand: 0,25 (m2.K/W); NLRS_C_Code_Brandklasse: A2-s1,d0; brandweerstand: REI 60 mits verwerkt tegen massief beton conform classificatierapport nr 16210B / 16211B; geluidsabsorbtie: max. 0,90; DoP: W4302APCPR; NLRS_C_content_creator: Knauf Insulation; NLRS_C_content_versie: V1.0
Type - Pset_Wall Schedule LOD400 - Assembly Code: 42.10; Type Image: Raster image: Heraklith A2 Afbouwpaneel.jpg; Model: Heraklith® | A2 afbouwpaneel is een A2 houtwolcementpaneel; Manufacturer: Knauf Insulation B.V.; URL: www.heraklith.nl; Description: A2 afbouwpaneel - 25mm; phone: +31(0)162-421245; email: customerservice.nl@knaufinsulation.com; product URL: https://heraklith.nl/houtwol-producten/a2-afbouwpaneel; warmteweerstand: 0,25 (m2.K/W); NLRS_C_Code_Brandklasse: A2-s1,d0; brandweerstand: REI 60 mits verwerkt tegen massief beton conform classificatierapport nr 16210B / 16211B; geluidsabsorbtie: max. 0,90; DoP: W4302APCPR; NLRS_C_content_creator: Knauf Insulation; NLRS_C_content_versie: V1.0; gewicht KG/M2: 11.5; panelen per pallet: 40; pallet m2: 28.8 m2; vezelbreedte: standaard 2mm optie: 1mm; kleur: standaard natuurtint optie: Wit (RAL9003) / RAL; Druksterkte kPa: 200; Chloride gehalte: Cl3; Tolerantie: Dikte (T): (T1) +3/-2; Tolerantie: Lengte (L): (L2) +3/-5; Tolerantie: Breedte (W): (W1) +3/-3; Tolerantie: Haaksheid (S): (S2) ≤2; Tolerantie: Vlakheid (P): (P1) ≤6; Randafwerking: Isolatie: n.v.t.; Randafwerking: Houtwol: Facet: 5mm; CE-codering: WW-EN 13168-L2-W1-T1-S2-P2-CS(10/Y)200-Cl3
Classification: 42.10 (Uniformat)
Pset_WallCommon - ExtendToStructure: no; LoadBearing: no
Wall Schedule LOD200 - Type: Basic Wall: NLRS_42_WA_Heraklith A2 afbouwpaneel 25x1200x600mm
Pset_Wall Schedule LOD400 - Type: Basic Wall: NLRS_42_WA_Heraklith A2 afbouwpaneel 25x1200x600mm

# IfcWallStandardCase: Basic Wall:NLRS_42_WA_Heraklith A2 afbouwpaneel 35x1000x600mm, Basic Wall:NLRS_42_WA_Heraklith A2 afbouwpaneel 35x1000x600mm:914116
In: 00 begane grond
Type - PredefinedType: STANDARD; Material: Heraklith A2 afbouwpaneel - Houtwollaag - 2000x600mm 35 mm
Type - Pset_ElementShading - Roughness: 304.8 mm
Type - Pset_ManufacturerTypeInformation - Manufacturer: Knauf Insulation B.V.
Type - Pset_ProductRequirements - Category: Walls
Type - Pset_QuantityTakeOff - Reference: Basic Wall:NLRS_42_WA_Heraklith A2 afbouwpaneel 35x1000x600mm
Type - Pset_ReinforcementBarPitchOfWall - Description: A2 afbouwpaneel - 35mm; Reference: Basic Wall:NLRS_42_WA_Heraklith A2 afbouwpaneel 35x1000x600mm
Type - Pset_WallCommon - IsExternal: no; Reference: Basic Wall:NLRS_42_WA_Heraklith A2 afbouwpaneel 35x1000x600mm; ThermalTransmittance: 24.2857 kg/K/s3
Type - Wall Schedule LOD200 - Assembly Code: 42.10; Type Image: Raster image: Heraklith A2 Afbouwpaneel.jpg; Model: Heraklith® | A2 afbouwpaneel is een A2 houtwolcementpaneel; Manufacturer: Knauf Insulation B.V.; URL: www.heraklith.nl; Description: A2 afbouwpaneel - 35mm; phone: +31(0)162-421245; email: customerservice.nl@knaufinsulation.com; product URL: https://heraklith.nl/houtwol-producten/a2-afbouwpaneel; warmteweerstand: 0,40 (m2.K/W); NLRS_C_Code_Brandklasse: A2-s1,d0; brandweerstand: REI 60 mits verwerkt tegen massief beton conform classificatierapport nr 16210B / 16211B; geluidsabsorbtie: 0,40; DoP: W4302APCPR; NLRS_C_content_creator: Knauf Insulation; NLRS_C_content_versie: V1.0
Type - Pset_Wall Schedule LOD400 - Assembly Code: 42.10; Type Image: Raster image: Heraklith A2 Afbouwpaneel.jpg; Model: Heraklith® | A2 afbouwpaneel is een A2 houtwolcementpaneel; Manufacturer: Knauf Insulation B.V.; URL: www.heraklith.nl; Description: A2 afbouwpaneel - 35mm; phone: +31(0)162-421245; email: customerservice.nl@knaufinsulation.com; product URL: https://heraklith.nl/houtwol-producten/a2-afbouwpaneel; warmteweerstand: 0,40 (m2.K/W); NLRS_C_Code_Brandklasse: A2-s1,d0; brandweerstand: REI 60 mits verwerkt tegen massief beton conform classificatierapport nr 16210B / 16211B; geluidsabsorbtie: 0,40; DoP: W4302APCPR; NLRS_C_content_creator: Knauf Insulation; NLRS_C_content_versie: V1.0; gewicht KG/M2: 14.5; panelen per pallet: 30; pallet m2: 18 m2; vezelbreedte: standaard 2mm optie: 1mm; kleur: standaard natuurtint optie: Wit (RAL9003) / RAL; Druksterkte kPa: 150; Chloride gehalte: Cl3; Tolerantie: Dikte (T): (T1) +3/-2; Tolerantie: Lengte (L): (L2) +3/-5; Tolerantie: Breedte (W): (W1) +3/-3; Tolerantie: Haaksheid (S): (S2) ≤2; Tolerantie: Vlakheid (P): (P1) ≤6; Randafwerking: Isolatie: n.v.t.; Randafwerking: Houtwol: Facet: 5mm; CE-codering: WW-EN 13168-L2-W1-T1-S2-P2-CS(10/Y)200-Cl3
Classification: 42.10 (Uniformat)
Pset_WallCommon - ExtendToStructure: no; LoadBearing: no
Wall Schedule LOD200 - Type: Basic Wall: NLRS_42_WA_Heraklith A2 afbouwpaneel 35x1000x600mm
Pset_Wall Schedule LOD400 - Type: Basic Wall: NLRS_42_WA_Heraklith A2 afbouwpaneel 35x1000x600mm
